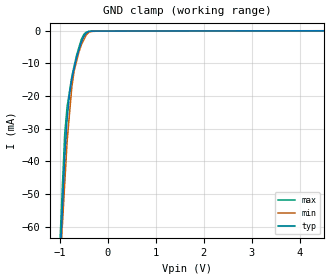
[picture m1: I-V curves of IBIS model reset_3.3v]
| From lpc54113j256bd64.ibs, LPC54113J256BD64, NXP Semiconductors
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[Model] reset_3.3v
Model_type Input
Vinl = 990.000mV
Vinh = 2.64000V
C_comp 1.42000pF 1.40000pF 1.44000pF
[Model spec]
| variable typ   min   max
Vinl  0.990  0.900  1.080
Vinh  2.640  2.400  2.880
| variable typ   min   max
[Voltage Range] 3.30000V 3.00000V 3.60000V
[POWER Clamp Reference] 3.30000V 3.00000V 3.60000V
[GND Clamp Reference] 0.00000V 0.00000V 0.00000V
[Temperature Range]   25   85   -40
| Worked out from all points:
|   GND clamp passes 1 mA (typ) near -0.46 V on its own axis
[GND Clamp]
-3.3V     -822.8mA   -671.3mA   -836.1mA
-900mV    -39.05mA   -47.08mA   -31.79mA
-850mV    -27.19mA   -34.07mA   -23.3mA
-800mV    -19.55mA   -25.55mA   -18.58mA
-750mV    -14.61mA   -17.02mA   -13.87mA
-700mV    -11.38mA   -12.11mA   -10.61mA
-600mV    -5.727mA   -6.359mA   -4.926mA
-550mV    -3.3mA     -4.161mA   -2.506mA
-450mV    -713uA     -1.236mA   -382uA
-350mV    -105.8uA   -196uA     -119.7uA
-175mV    -73.09uA   -68.51uA   -73.7uA
6.6V      69.2uA     79.61uA    61.81uA
[POWER Clamp]
-3.3V     0A         0A         0A
6.6V      0A         0A         0A
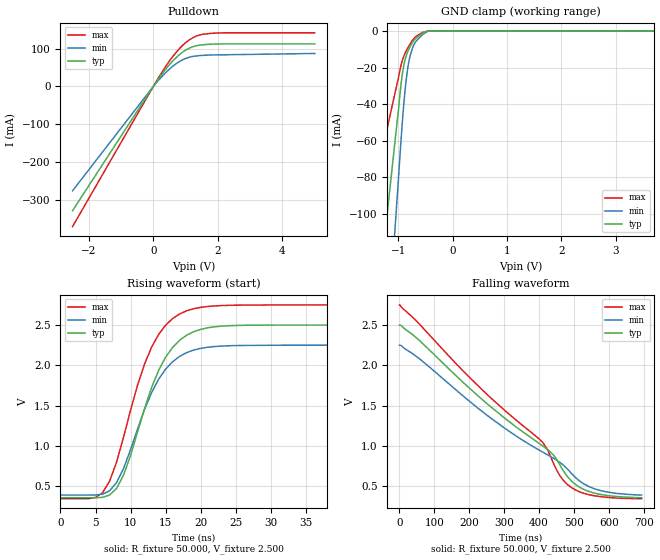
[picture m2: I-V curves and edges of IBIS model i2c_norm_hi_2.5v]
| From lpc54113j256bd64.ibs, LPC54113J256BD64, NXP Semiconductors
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[Model]   i2c_norm_hi_2.5v
Model_type I/O_open_drain
Vinl=4.000E-01
Vinh=1.500E+00
Vref=2.500E+00
Rref=1.000E+03
Cref=0.000E+00
Vmeas=1.250E+00
C_comp   9.060E-12   8.700E-12   9.420E-12
[Voltage Range]   2.500E+00   2.250E+00   2.750E+00
[POWER Clamp Reference]   2.500E+00   2.250E+00   2.750E+00
[GND Clamp Reference]   0.000E+00   0.000E+00   0.000E+00
[Pullup Reference]   2.500E+00   2.250E+00   2.750E+00
[Pulldown Reference]   0.000E+00   0.000E+00   0.000E+00
[Temperature Range]   25   105   -40
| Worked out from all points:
|   slope of the pulldown table from 0 to 0.375 V, typ, clamps not added: 8.44 ohm
|   GND clamp passes 1 mA (typ) near -0.53 V on its own axis
|   rising waveform, R_fixture 50.000, V_fixture 2.500: 20-80 % time 5.21ns typ, 5.22ns min, 5.18ns max; typ from 0.359 V to 2.5 V
|   falling waveform, R_fixture 50.000, V_fixture 2.500: 20-80 % time 342ns typ, 356ns min, 328ns max; typ from 2.5 V to 0.359 V
[GND Clamp]
-2.5V     -459.3mA   -735.3mA   -227.3mA
-1.02V    -49.73mA   -91.54mA   -28.76mA
-1V       -44.89mA   -83.18mA   -26.49mA
-960mV    -32.38mA   -65.07mA   -20.3mA
-920mV    -22.82mA   -48.44mA   -15.76mA
-860mV    -14.29mA   -28.61mA   -11.29mA
-820mV    -10.94mA   -19.54mA   -9.041mA
-780mV    -8.49mA    -13.47mA   -7.044mA
-720mV    -5.59mA    -8.124mA   -4.402mA
-560mV    -1.408mA   -2.144mA   -897uA
-440mV    0A         0A         0A
5V        0A         0A         0A
[Pulldown]
-2.5V     -328.1mA   -275.5mA   -370.2mA
160mV     20.09mA    16.31mA    23.08mA
600mV     67.25mA    53.36mA    78.96mA
860mV     87.65mA    68.38mA    104.5mA
1.04V     98.07mA    75.37mA    118.5mA
1.24V     105.4mA    79.69mA    129.4mA
1.42V     108.9mA    81.45mA    135.7mA
1.86V     112mA      83.37mA    140.8mA
5V        112.5mA    87.24mA    141.8mA
[Rising Waveform]
R_fixture = 50.000
V_fixture = 2.500
V_fixture_min = 2.250
V_fixture_max = 2.750
|  time   V(typ)   V(min)   V(max)
0s        359.4mV    392.6mV    347.6mV
5ns       359.1mV    393mV      363.3mV
7ns       392.5mV    444.7mV    563.3mV
8ns       474.9mV    546.8mV    799.4mV
11ns      1.175V     1.213V     1.756V
13ns      1.726V     1.663V     2.227V
15ns      2.102V     1.954V     2.499V
17ns      2.312V     2.112V     2.638V
23ns      2.487V     2.24V      2.742V
53ns      2.5V       2.25V      2.75V
[Falling Waveform]
R_fixture = 50.000
V_fixture = 2.500
V_fixture_min = 2.250
V_fixture_max = 2.750
|  time   V(typ)   V(min)   V(max)
0s        2.5V       2.25V      2.75V
57ns      2.31V      2.084V     2.514V
236ns     1.582V     1.433V     1.702V
410ns     1.004V     926.7mV    1.048V
424ns     958mV      892mV      960.4mV
457ns     785.9mV    805.2mV    652.6mV
484ns     608.6mV    702.6mV    513.8mV
519ns     483.2mV    557.7mV    427.8mV
559ns     416.7mV    470.4mV    383.6mV
694ns     359.4mV    392.6mV    347.6mV
[Ramp]
dV/dt_r   1.2844E+00/5.1580E-09   1.1140E+00/5.1680E-09   1.3766E+00/5.1440E-09
dV/dt_f   1.2844E+00/3.4247E-07   1.1140E+00/3.5622E-07   1.3766E+00/3.2824E-07
R_load = 50
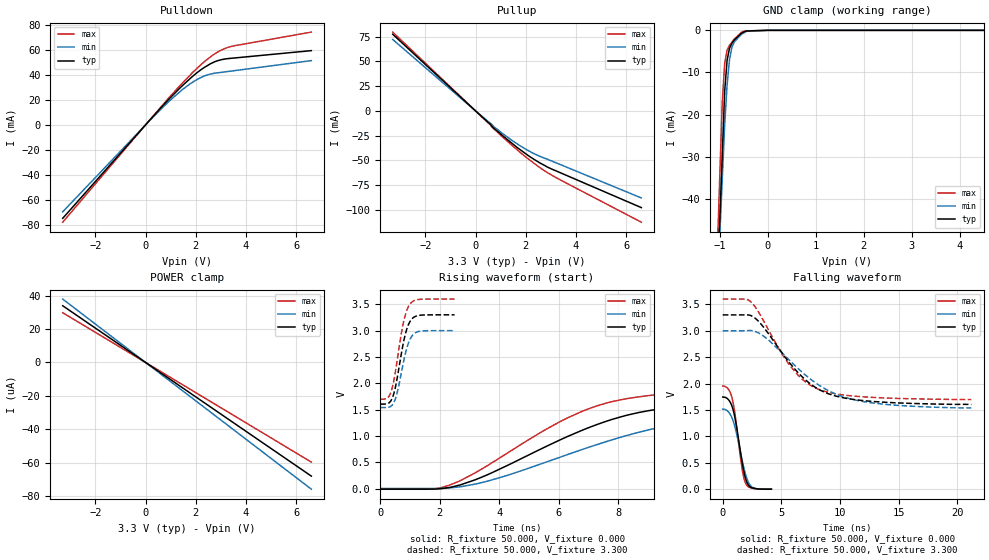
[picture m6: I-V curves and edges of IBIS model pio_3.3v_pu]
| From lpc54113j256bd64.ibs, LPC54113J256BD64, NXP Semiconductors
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[Model]   pio_3.3v_pu
Model_type I/O
Vinl=8.000E-01
Vinh=2.000E+00
Vref=0.000E+00
Rref=1.000E+06
Cref=2.000E-11
Vmeas=1.650E+00
C_comp   9.060E-13   8.700E-13   9.240E-13
[Voltage Range]   3.300E+00   3.000E+00   3.600E+00
[POWER Clamp Reference]   3.300E+00   3.000E+00   3.600E+00
[GND Clamp Reference]   0.000E+00   0.000E+00   0.000E+00
[Pullup Reference]   3.300E+00   3.000E+00   3.600E+00
[Pulldown Reference]   0.000E+00   0.000E+00   0.000E+00
[Temperature Range]   25   105   -40
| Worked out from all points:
|   slope of the pulldown table from 0 to 0.495 V, typ, clamps not added: 44.8 ohm
|   slope of the pullup table from 0 to 0.495 V, typ, clamps not added: 43.6 ohm
|   GND clamp passes 1 mA (typ) near -0.58 V on its own axis
|   rising waveform, R_fixture 50.000, V_fixture 0.000: 20-80 % time 4.35ns typ, 5.29ns min, 3.74ns max; typ from -0.012 V to 1.73 V
|   falling waveform, R_fixture 50.000, V_fixture 0.000: 20-80 % time 788ps typ, 920ps min, 704ps max; typ from 1.75 V to 0.002 V
|   rising waveform, R_fixture 50.000, V_fixture 3.300: 20-80 % time 341ps typ, 343ps min, 341ps max; typ from 1.6 V to 3.3 V
|   falling waveform, R_fixture 50.000, V_fixture 3.300: 20-80 % time 3.95ns typ, 4.88ns min, 3.41ns max; typ from 3.3 V to 1.6 V
[GND Clamp]
-3.3V     -735mA     -639.7mA   -812.5mA
-950mV    -29.46mA   -35.33mA   -17.06mA
-900mV    -14.45mA   -22.48mA   -7.838mA
-850mV    -7.167mA   -13.05mA   -4.739mA
-800mV    -4.27mA    -7.013mA   -3.572mA
-750mV    -3.082mA   -4.05mA    -2.806mA
-700mV    -2.312mA   -2.747mA   -2.039mA
-550mV    -689.6uA   -927.9uA   -494.3uA
-500mV    -362.1uA   -605.4uA   -236.4uA
-400mV    -150.5uA   -141.3uA   -108.2uA
0V        0A         0A         0A
6.6V      0A         0A         0A
[Power Clamp]
-3.3V     34uA       38uA       29.8uA
0V        0A         0A         0A
6.6V      -68.1uA    -75.93uA   -59.69uA
[Pullup]
-3.3V     77.49mA    72.2mA     79.65mA
760mV     -18.12mA   -16.61mA   -18.86mA
1.46V     -32.91mA   -29.95mA   -34.98mA
2.12V     -45.48mA   -40.34mA   -48.91mA
2.58V     -52.8mA    -46.08mA   -57.61mA
3.14V     -59.87mA   -51.73mA   -66.48mA
6.6V      -97.67mA   -87.89mA   -112.4mA
[Pulldown]
-3.3V     -74.59mA   -69.4mA    -77.67mA
140mV     3.186mA    2.948mA    3.327mA
940mV     20.73mA    18.9mA     21.9mA
1.44V     30.86mA    27.69mA    32.8mA
1.78V     37.07mA    32.83mA    39.81mA
2.24V     44.5mA     38.17mA    48.65mA
2.78V     50.6mA     41.38mA    57.01mA
3.34V     53.01mA    42.75mA    62.23mA
6.6V      59.25mA    51.3mA     74.05mA
[Rising Waveform]
R_fixture = 50.000
V_fixture = 0.000
V_fixture_min = 0.000
V_fixture_max = 0.000
|  time   V(typ)   V(min)   V(max)
0s        -11.6mV    1.512mV    -11.05mV
1.75ns    -10.32mV   1.179mV    -6.202mV
2.35ns    23.6mV     13.36mV    69.84mV
3.7ns     286.1mV    155.1mV    469.2mV
6.3ns     989.1mV    645.9mV    1.343V
7.3ns     1.218V     837.1mV    1.572V
8.35ns    1.4V       1.017V     1.713V
10.15ns   1.565V     1.243V     1.825V
12.3ns    1.648V     1.381V     1.882V
20.7ns    1.733V     1.517V     1.939V
[Falling Waveform]
R_fixture = 50.000
V_fixture = 0.000
V_fixture_min = 0.000
V_fixture_max = 0.000
|  time   V(typ)   V(min)   V(max)
0s        1.745V     1.517V     1.953V
450ps     1.705V     1.473V     1.902V
800ps     1.566V     1.347V     1.722V
1.1ns     1.287V     1.13V      1.339V
1.65ns    519.7mV    556.1mV    393.4mV
1.8ns     340.3mV    408.5mV    219.8mV
1.95ns    202.7mV    281.2mV    114.1mV
2.2ns     76.07mV    127.9mV    44.24mV
2.55ns    24.78mV    33.01mV    16.79mV
4.15ns    1.582mV    1.512mV    1.573mV
[Rising Waveform]
R_fixture = 50.000
V_fixture = 3.300
V_fixture_min = 3.000
V_fixture_max = 3.600
|  time   V(typ)   V(min)   V(max)
0s        1.605V     1.538V     1.697V
250ps     1.615V     1.542V     1.724V
400ps     1.711V     1.584V     1.907V
550ps     2.039V     1.781V     2.367V
750ps     2.691V     2.319V     3.076V
850ps     2.949V     2.579V     3.315V
1ns       3.174V     2.835V     3.506V
1.15ns    3.262V     2.948V     3.573V
1.3ns     3.29V      2.985V     3.593V
2.5ns     3.3V       3V         3.6V
[Falling Waveform]
R_fixture = 50.000
V_fixture = 3.300
V_fixture_min = 3.000
V_fixture_max = 3.600
|  time   V(typ)   V(min)   V(max)
0s        3.3V       3V         3.6V
2.4ns     3.287V     3.004V     3.548V
3.45ns    3.078V     2.905V     3.202V
4.85ns    2.646V     2.628V     2.635V
5.8ns     2.365V     2.418V     2.323V
6.9ns     2.102V     2.191V     2.059V
8.15ns    1.896V     1.979V     1.894V
9.75ns    1.758V     1.791V     1.802V
12.1ns    1.675V     1.655V     1.747V
21.2ns    1.605V     1.538V     1.697V
[Ramp]
dV/dt_r   1.0470E+00/4.3389E-09   9.0819E-01/5.2888E-09   1.1703E+00/3.7398E-09
dV/dt_f   1.0173E+00/3.9512E-09   8.7689E-01/4.8527E-09   1.1419E+00/3.3989E-09
R_load = 50
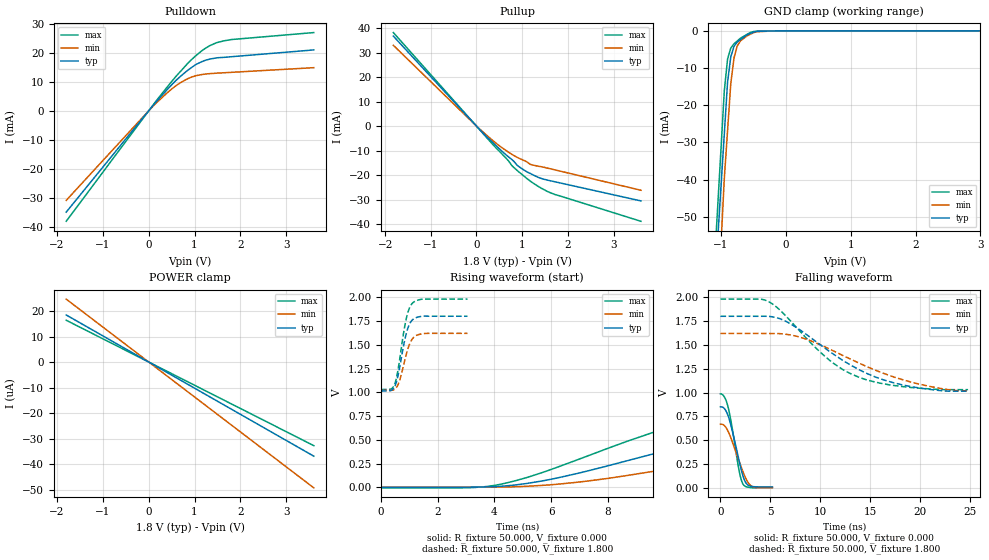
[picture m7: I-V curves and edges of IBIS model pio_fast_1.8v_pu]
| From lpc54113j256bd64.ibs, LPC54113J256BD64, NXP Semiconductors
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[Model]   pio_fast_1.8v_pu
Model_type I/O
Vinl=4.000E-01
Vinh=1.500E+00
Vref=0.000E+00
Rref=1.000E+06
Cref=2.000E-11
Vmeas=9.000E-01
C_comp   9.060E-12   8.700E-12   9.420E-12
[Voltage Range]   1.800E+00   1.620E+00   1.980E+00
[POWER Clamp Reference]   1.800E+00   1.620E+00   1.980E+00
[GND Clamp Reference]   0.000E+00   0.000E+00   0.000E+00
[Pullup Reference]   1.800E+00   1.620E+00   1.980E+00
[Pulldown Reference]   0.000E+00   0.000E+00   0.000E+00
[Temperature Range]   25   105   -40
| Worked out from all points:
|   slope of the pulldown table from 0 to 0.27 V, typ, clamps not added: 54.4 ohm
|   slope of the pullup table from 0 to 0.27 V, typ, clamps not added: 52.3 ohm
|   GND clamp passes 1 mA (typ) near -0.59 V on its own axis
|   rising waveform, R_fixture 50.000, V_fixture 0.000: 20-80 % time 7.6ns typ, 8.94ns min, 6.14ns max; typ from 0.001 V to 0.845 V
|   falling waveform, R_fixture 50.000, V_fixture 0.000: 20-80 % time 1.13ns typ, 1.38ns min, 947ps max; typ from 0.85 V to 0.009 V
|   rising waveform, R_fixture 50.000, V_fixture 1.800: 20-80 % time 315ps typ, 326ps min, 312ps max; typ from 1.01 V to 1.8 V
|   falling waveform, R_fixture 50.000, V_fixture 1.800: 20-80 % time 7.15ns typ, 8.09ns min, 5.95ns max; typ from 1.8 V to 1.01 V
[GND Clamp]
-1.8V     -263.7mA   -335.6mA   -275.8mA
-950mV    -27.75mA   -39.74mA   -16.17mA
-900mV    -13.87mA   -26.94mA   -7.61mA
-850mV    -6.971mA   -14.14mA   -4.632mA
-800mV    -4.156mA   -7.28mA    -3.484mA
-750mV    -2.988mA   -4.044mA   -2.731mA
-700mV    -2.361mA   -2.687mA   -1.978mA
-600mV    -1.106mA   -1.378mA   -966uA
-550mV    -718uA     -946.2uA   -460.3uA
-450mV    -144.5uA   -255.5uA   -88.61uA
0V        0A         0A         0A
3.6V      0A         0A         0A
[Power Clamp]
-1.8V     18.45uA    24.66uA    16.39uA
0V        0A         0A         0A
3.6V      -36.9uA    -49.32uA   -32.77uA
[Pullup]
-1.82V    36.68mA    32.95mA    38.14mA
60mV      -1.186mA   -1.045mA   -1.256mA
520mV     -9.605mA   -8.289mA   -10.63mA
680mV     -12.23mA   -10.39mA   -13.75mA
780mV     -13.74mA   -11.58mA   -16.2mA
900mV     -16.13mA   -12.84mA   -18.25mA
1V        -17.45mA   -13.7mA    -19.78mA
1.2V      -19.53mA   -15.73mA   -22.73mA
1.42V     -21.36mA   -16.58mA   -25.34mA
1.62V     -22.32mA   -17.43mA   -27.21mA
3.6V      -30.52mA   -26.17mA   -38.83mA
[Pulldown]
-1.8V     -34.9mA    -30.86mA   -38.06mA
0V        0A         0A         0A
400mV     7.25mA     6.14mA     8.117mA
600mV     10.52mA    8.704mA    11.94mA
820mV     13.55mA    10.8mA     15.78mA
1.02V     15.83mA    12.03mA    18.86mA
1.16V     16.92mA    12.47mA    20.67mA
1.32V     17.75mA    12.77mA    22.31mA
1.48V     18.2mA     12.94mA    23.43mA
1.8V      18.6mA     13.23mA    24.51mA
3.6V      20.95mA    14.84mA    26.92mA
[Rising Waveform]
R_fixture = 50.000
V_fixture = 0.000
V_fixture_min = 0.000
V_fixture_max = 0.000
|  time   V(typ)   V(min)   V(max)
0s        997.3uV    1.378mV    -5.148mV
3.15ns    2.024mV    1.625mV    -3.175mV
4.25ns    12.16mV    3.223mV    34.99mV
6.25ns    101.2mV    33.85mV    215.6mV
10.3ns    405.7mV    203.6mV    644.2mV
11.85ns   515.3mV    283.4mV    763.1mV
13.5ns    613.2mV    364.9mV    849.4mV
16ns      719mV      471.5mV    919.6mV
18.35ns   778mV      549.8mV    952.7mV
25.05ns   844.6mV    666.9mV    979.7mV
[Falling Waveform]
R_fixture = 50.000
V_fixture = 0.000
V_fixture_min = 0.000
V_fixture_max = 0.000
|  time   V(typ)   V(min)   V(max)
0s        849.9mV    666.9mV    985.7mV
400ps     830.4mV    652.4mV    952mV
750ps     759.7mV    596.2mV    852.3mV
1.15ns    611.8mV    492.7mV    642mV
1.85ns    291.4mV    285.4mV    189.8mV
2.05ns    202.3mV    226.4mV    95.82mV
2.25ns    126.3mV    169.7mV    40.35mV
2.6ns     43.82mV    85.56mV    10.34mV
3.15ns    14.29mV    15.08mV    189.3uV
5.2ns     9.033mV    1.378mV    951.5uV
[Rising Waveform]
R_fixture = 50.000
V_fixture = 1.800
V_fixture_min = 1.620
V_fixture_max = 1.980
|  time   V(typ)   V(min)   V(max)
0s        1.014V     1.019V     1.03V
350ps     1.019V     1.02V      1.035V
500ps     1.069V     1.035V     1.099V
650ps     1.246V     1.116V     1.327V
800ps     1.495V     1.287V     1.629V
900ps     1.628V     1.408V     1.785V
1ns       1.714V     1.501V     1.884V
1.1ns     1.759V     1.559V     1.935V
1.55ns    1.801V     1.619V     1.98V
3.05ns    1.8V       1.62V      1.98V
[Falling Waveform]
R_fixture = 50.000
V_fixture = 1.800
V_fixture_min = 1.620
V_fixture_max = 1.980
|  time   V(typ)   V(min)   V(max)
0s        1.8V       1.62V      1.98V
4ns       1.8V       1.62V      1.98V
4.95ns    1.798V     1.619V     1.946V
7.05ns    1.718V     1.603V     1.747V
10.75ns   1.444V     1.464V     1.354V
12.2ns    1.341V     1.391V     1.244V
13.95ns   1.236V     1.305V     1.157V
18.75ns   1.069V     1.119V     1.056V
22.65ns   1.015V     1.032V     1.03V
24.8ns    1.014V     1.019V     1.03V
[Ramp]
dV/dt_r   5.0453E-01/7.5936E-09   4.0062E-01/8.9309E-09   5.9090E-01/6.1396E-09
dV/dt_f   4.7142E-01/7.1409E-09   3.6076E-01/8.0730E-09   5.6989E-01/5.9432E-09
R_load = 50
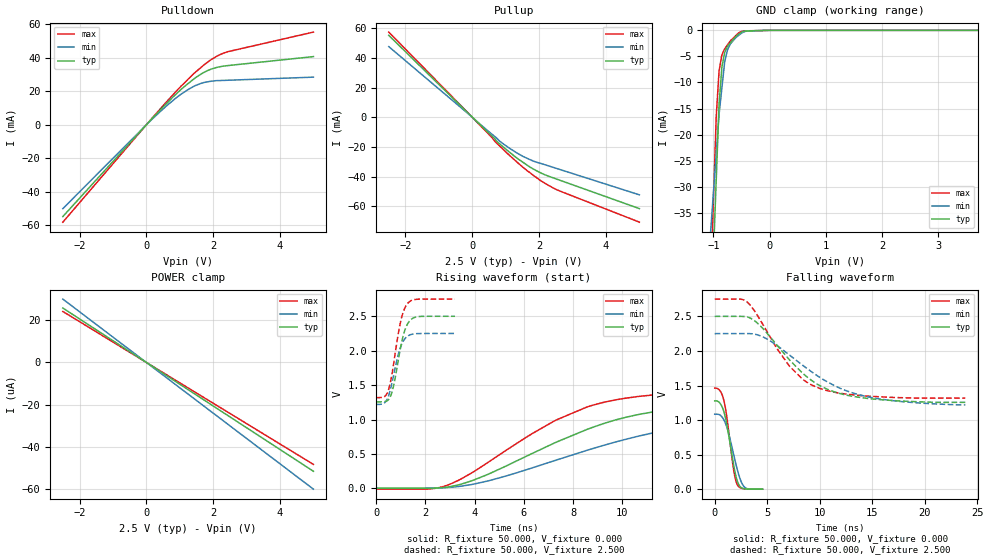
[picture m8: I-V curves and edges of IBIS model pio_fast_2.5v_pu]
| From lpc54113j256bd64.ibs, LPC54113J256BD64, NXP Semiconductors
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[Model]   pio_fast_2.5v_pu
Model_type I/O
Vinl=4.000E-01
Vinh=1.500E+00
Vref=0.000E+00
Rref=1.000E+06
Cref=2.000E-11
Vmeas=1.250E+00
C_comp   9.060E-12   8.700E-12   9.420E-12
[Voltage Range]   2.500E+00   2.250E+00   2.750E+00
[POWER Clamp Reference]   2.500E+00   2.250E+00   2.750E+00
[GND Clamp Reference]   0.000E+00   0.000E+00   0.000E+00
[Pullup Reference]   2.500E+00   2.250E+00   2.750E+00
[Pulldown Reference]   0.000E+00   0.000E+00   0.000E+00
[Temperature Range]   25   105   -40
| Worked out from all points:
|   slope of the pulldown table from 0 to 0.375 V, typ, clamps not added: 46.9 ohm
|   slope of the pullup table from 0 to 0.375 V, typ, clamps not added: 46.2 ohm
|   GND clamp passes 1 mA (typ) near -0.58 V on its own axis
|   rising waveform, R_fixture 50.000, V_fixture 0.000: 20-80 % time 5.16ns typ, 6.52ns min, 4.28ns max; typ from 0.001 V to 1.28 V
|   falling waveform, R_fixture 50.000, V_fixture 0.000: 20-80 % time 884ps typ, 1.06ns min, 766ps max; typ from 1.28 V to 0.001 V
|   rising waveform, R_fixture 50.000, V_fixture 2.500: 20-80 % time 409ps typ, 413ps min, 406ps max; typ from 1.26 V to 2.5 V
|   falling waveform, R_fixture 50.000, V_fixture 2.500: 20-80 % time 4.91ns typ, 6.27ns min, 4.01ns max; typ from 2.5 V to 1.26 V
[GND Clamp]
-2.5V     -475.7mA   -255.8mA   -509.6mA
-950mV    -28.56mA   -23.6mA    -16.48mA
-900mV    -14.13mA   -16.11mA   -7.789mA
-850mV    -7.08mA    -11.07mA   -4.709mA
-800mV    -4.224mA   -6.027mA   -3.542mA
-750mV    -3.043mA   -3.75mA    -2.78mA
-700mV    -2.406mA   -2.615mA   -2.018mA
-600mV    -1.132mA   -1.373mA   -993uA
-500mV    -345.9uA   -523.1uA   -221.8uA
-400mV    -135.5uA   -126.9uA   -93.31uA
0V        0A         0A         0A
5V        0A         0A         0A
[Power Clamp]
-2.5V     25.73uA    29.96uA    24.11uA
0V        0A         0A         0A
5V        -51.47uA   -59.93uA   -48.22uA
[Pullup]
-2.5V     55.17mA    47.6mA     57.37mA
0V        0A         0A         0A
820mV     -17.99mA   -16.12mA   -19.39mA
1.4V      -28.61mA   -24.91mA   -31.48mA
1.94V     -36.26mA   -30.42mA   -40.98mA
2.26V     -39.55mA   -32.62mA   -45.65mA
2.54V     -41.8mA    -34.63mA   -48.95mA
5V        -61.57mA   -52.31mA   -70.72mA
[Pulldown]
-2.5V     -54.85mA   -50.1mA    -58.2mA
0V        0A         0A         0A
500mV     10.6mA     9.452mA    11.41mA
1.04V     21.22mA    18.33mA    23.13mA
1.42V     27.38mA    22.99mA    30.62mA
1.64V     30.38mA    24.79mA    34.37mA
1.84V     32.48mA    25.72mA    37.54mA
2.12V     34.38mA    26.41mA    41.13mA
2.44V     35.42mA    26.64mA    43.72mA
5V        40.78mA    28.5mA     55.43mA
[Rising Waveform]
R_fixture = 50.000
V_fixture = 0.000
V_fixture_min = 0.000
V_fixture_max = 0.000
|  time   V(typ)   V(min)   V(max)
0s        1.249mV    1.217mV    -10.9mV
2.1ns     1.222mV    2.349mV    -9.946mV
2.9ns     19.48mV    12.39mV    47.42mV
4.5ns     197.9mV    104.8mV    367mV
7.35ns    676.6mV    415.2mV    999.4mV
8.6ns     861.4mV    556.9mV    1.186V
9.85ns    1.006V     685.9mV    1.294V
11.6ns    1.129V     832.3mV    1.368V
14.65ns   1.221V     977.3mV    1.423V
23.65ns   1.278V     1.085V     1.452V
[Falling Waveform]
R_fixture = 50.000
V_fixture = 0.000
V_fixture_min = 0.000
V_fixture_max = 0.000
|  time   V(typ)   V(min)   V(max)
0s        1.278V     1.085V     1.462V
500ps     1.244V     1.073V     1.425V
900ps     1.107V     995.2mV    1.265V
1.2ns     897.7mV    874.3mV    992.1mV
1.8ns     352.8mV    503.4mV    282.2mV
1.95ns    236mV      405.9mV    159.7mV
2.15ns    118.5mV    283.4mV    65.57mV
2.55ns    21.09mV    98.55mV    14.59mV
2.9ns     5.062mV    23.42mV    4.224mV
4.55ns    1.249mV    1.217mV    1.229mV
[Rising Waveform]
R_fixture = 50.000
V_fixture = 2.500
V_fixture_min = 2.250
V_fixture_max = 2.750
|  time   V(typ)   V(min)   V(max)
0s        1.257V     1.22V      1.318V
400ps     1.265V     1.268V     1.355V
500ps     1.289V     1.344V     1.432V
600ps     1.355V     1.47V      1.581V
750ps     1.566V     1.718V     1.912V
950ps     1.972V     2.011V     2.354V
1.1ns     2.223V     2.14V      2.565V
1.25ns    2.374V     2.205V     2.675V
1.65ns    2.492V     2.248V     2.747V
3.2ns     2.5V       2.25V      2.75V
[Falling Waveform]
R_fixture = 50.000
V_fixture = 2.500
V_fixture_min = 2.250
V_fixture_max = 2.750
|  time   V(typ)   V(min)   V(max)
0s        2.5V       2.25V      2.75V
2.5ns     2.5V       2.25V      2.749V
3.1ns     2.491V     2.251V     2.705V
4.7ns     2.305V     2.195V     2.352V
7.1ns     1.873V     1.942V     1.783V
8.35ns    1.68V      1.795V     1.593V
9.7ns     1.524V     1.648V     1.475V
12.25ns   1.371V     1.44V      1.381V
14.9ns    1.307V     1.327V     1.343V
23.85ns   1.257V     1.22V      1.318V
[Ramp]
dV/dt_r   7.6469E-01/5.1563E-09   6.4858E-01/6.5173E-09   8.7806E-01/4.2483E-09
dV/dt_f   7.4600E-01/4.9050E-09   6.1833E-01/6.2646E-09   8.5930E-01/3.9848E-09
R_load = 50
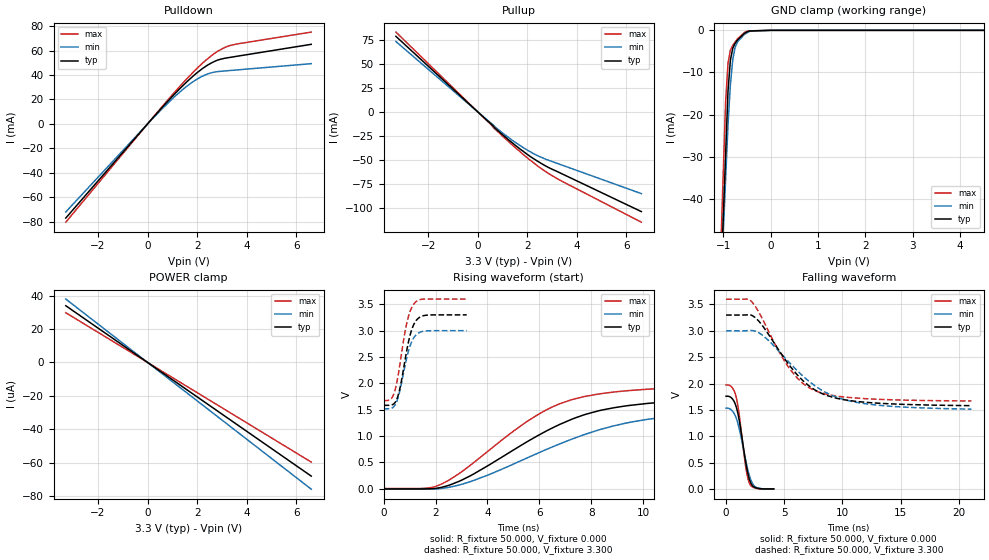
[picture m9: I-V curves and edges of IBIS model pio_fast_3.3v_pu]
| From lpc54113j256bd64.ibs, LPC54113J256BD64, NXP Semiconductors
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[Model]   pio_fast_3.3v_pu
Model_type I/O
Vinl=8.000E-01
Vinh=2.000E+00
Vref=0.000E+00
Rref=1.000E+06
Cref=2.000E-11
Vmeas=1.650E+00
C_comp   9.060E-12   8.700E-12   9.420E-12
[Voltage Range]   3.300E+00   3.000E+00   3.600E+00
[POWER Clamp Reference]   3.300E+00   3.000E+00   3.600E+00
[GND Clamp Reference]   0.000E+00   0.000E+00   0.000E+00
[Pullup Reference]   3.300E+00   3.000E+00   3.600E+00
[Pulldown Reference]   0.000E+00   0.000E+00   0.000E+00
[Temperature Range]   25   105   -40
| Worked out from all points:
|   slope of the pulldown table from 0 to 0.495 V, typ, clamps not added: 43.7 ohm
|   slope of the pullup table from 0 to 0.495 V, typ, clamps not added: 42.9 ohm
|   GND clamp passes 1 mA (typ) near -0.58 V on its own axis
|   rising waveform, R_fixture 50.000, V_fixture 0.000: 20-80 % time 4.01ns typ, 4.87ns min, 3.42ns max; typ from -0.007 V to 1.75 V
|   falling waveform, R_fixture 50.000, V_fixture 0.000: 20-80 % time 778ps typ, 900ps min, 693ps max; typ from 1.76 V to 0.002 V
|   rising waveform, R_fixture 50.000, V_fixture 3.300: 20-80 % time 406ps typ, 410ps min, 403ps max; typ from 1.58 V to 3.3 V
|   falling waveform, R_fixture 50.000, V_fixture 3.300: 20-80 % time 3.75ns typ, 4.6ns min, 3.19ns max; typ from 3.3 V to 1.58 V
[GND Clamp]
-3.3V     -735mA     -639.7mA   -812.5mA
-950mV    -29.46mA   -35.33mA   -17.06mA
-900mV    -14.45mA   -22.48mA   -7.838mA
-850mV    -7.167mA   -13.05mA   -4.739mA
-800mV    -4.27mA    -7.013mA   -3.572mA
-750mV    -3.082mA   -4.05mA    -2.806mA
-700mV    -2.312mA   -2.747mA   -2.039mA
-550mV    -689.6uA   -927.9uA   -494.3uA
-500mV    -362.1uA   -605.4uA   -236.4uA
-400mV    -150.5uA   -141.3uA   -108.2uA
0V        0A         0A         0A
6.6V      0A         0A         0A
[Power Clamp]
-3.3V     34uA       38uA       29.8uA
0V        0A         0A         0A
6.6V      -68.1uA    -75.93uA   -59.69uA
[Pullup]
-3.3V     78.3mA     72.94mA    82.7mA
720mV     -17.43mA   -16.13mA   -18.38mA
1.36V     -31.35mA   -28.83mA   -33.53mA
1.82V     -40.62mA   -36.76mA   -43.91mA
2.5V      -52.53mA   -46.42mA   -57.65mA
3.22V     -62.03mA   -53.52mA   -69.47mA
6.6V      -103.4mA   -84.74mA   -114.4mA
[Pulldown]
-3.3V     -77.06mA   -72.09mA   -80.46mA
140mV     3.263mA    3.027mA    3.421mA
1.04V     23.4mA     21.38mA    24.81mA
1.46V     32mA       28.83mA    34.24mA
1.9V      40.22mA    35.44mA    43.55mA
2.22V     45.34mA    39.08mA    49.76mA
2.64V     50.5mA     42.1mA     56.82mA
3.12V     53.7mA     43.29mA    62.54mA
3.54V     55.09mA    44.01mA    65.14mA
6.6V      65.07mA    49.25mA    75.08mA
[Rising Waveform]
R_fixture = 50.000
V_fixture = 0.000
V_fixture_min = 0.000
V_fixture_max = 0.000
|  time   V(typ)   V(min)   V(max)
0s        -6.972mV   -11.77mV   1.55mV
1.65ns    -6.031mV   -11.97mV   7.215mV
2.2ns     18.82mV    -80.67uV   77.82mV
3.35ns    244.8mV    133.1mV    446.1mV
5.9ns     994.4mV    663.1mV    1.392V
6.8ns     1.222V     850.9mV    1.614V
7.8ns     1.413V     1.036V     1.755V
9.5ns     1.581V     1.26V      1.863V
11.85ns   1.675V     1.403V     1.925V
20.45ns   1.751V     1.522V     1.975V
[Falling Waveform]
R_fixture = 50.000
V_fixture = 0.000
V_fixture_min = 0.000
V_fixture_max = 0.000
|  time   V(typ)   V(min)   V(max)
0s        1.76V      1.536V     1.975V
550ps     1.708V     1.477V     1.917V
900ps     1.54V      1.33V      1.715V
1.15ns    1.281V     1.128V     1.377V
1.7ns     497.4mV    533.1mV    406.8mV
1.85ns    320.2mV    384.7mV    225.2mV
2ns       187.5mV    259.8mV    114.4mV
2.25ns    68.86mV    114.5mV    41.7mV
2.55ns    24.57mV    35.98mV    15.62mV
4.1ns     1.562mV    1.492mV    1.55mV
[Rising Waveform]
R_fixture = 50.000
V_fixture = 3.300
V_fixture_min = 3.000
V_fixture_max = 3.600
|  time   V(typ)   V(min)   V(max)
0s        1.581V     1.514V     1.67V
300ps     1.587V     1.525V     1.711V
400ps     1.612V     1.559V     1.806V
500ps     1.688V     1.647V     1.996V
650ps     1.957V     1.914V     2.438V
900ps     2.65V      2.506V     3.163V
1.05ns    2.971V     2.756V     3.408V
1.2ns     3.154V     2.893V     3.529V
1.6ns     3.291V     2.993V     3.6V
3.2ns     3.3V       3V         3.6V
[Falling Waveform]
R_fixture = 50.000
V_fixture = 3.300
V_fixture_min = 3.000
V_fixture_max = 3.600
|  time   V(typ)   V(min)   V(max)
0s        3.3V       3V         3.6V
2.2ns     3.295V     3.007V     3.555V
3.2ns     3.078V     2.905V     3.196V
4.5ns     2.646V     2.624V     2.624V
5.4ns     2.36V      2.408V     2.303V
6.5ns     2.079V     2.164V     2.023V
7.65ns    1.878V     1.957V     1.866V
9.3ns     1.733V     1.758V     1.771V
11.7ns    1.651V     1.627V     1.718V
21.1ns    1.581V     1.514V     1.67V
[Ramp]
dV/dt_r   1.0546E+00/4.0018E-09   9.2039E-01/4.8626E-09   1.1824E+00/3.4156E-09
dV/dt_f   1.0315E+00/3.7458E-09   8.9139E-01/4.5835E-09   1.1580E+00/3.1818E-09
R_load = 50
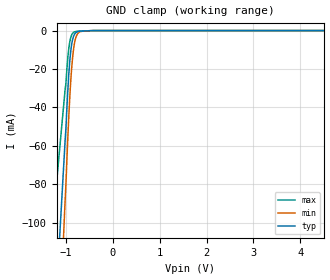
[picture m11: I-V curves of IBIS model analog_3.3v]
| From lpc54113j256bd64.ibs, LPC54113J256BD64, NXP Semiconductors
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[Model] analog_3.3v
Model_type Terminator
C_comp  0.906pF 0.870pF 0.942pF
| variable typ   min   max
[Voltage Range]   3.30000V  3.00000V  3.60000V
[POWER Clamp Reference]  3.30000V  3.00000V  3.60000V
[GND Clamp Reference]   0.00000V  0.00000V  0.00000V
[Temperature Range]   25   85   -40
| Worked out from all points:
|   GND clamp passes 1 mA (typ) near -0.78 V on its own axis
[GND Clamp]
-3.3V     -1.042A    -1.351A    -636.8mA
-1.02V    -58.5mA    -90.25mA   -31.49mA
-1V       -51.02mA   -79.97mA   -27.36mA
-960mV    -31.4mA    -56.23mA   -14.32mA
-920mV    -16.62mA   -35.82mA   -6.182mA
-880mV    -7.597mA   -20.36mA   -2.426mA
-860mV    -4.932mA   -14.66mA   -1.531mA
-820mV    -2.058mA   -6.953mA   -711.8uA
-780mV    -937.2uA   -3.049mA   -455.4uA
-720mV    -390.3uA   -907.4uA   -313.1uA
-440mV    -30.64uA   -39.2uA    -26.15uA
6.6V      0A         0A         0A
[Power Clamp]
-3.3V     0A         0A         0A
0V        0A         0A         0A
3.3V      0A         0A         0A
6.6V      0A         0A         0A
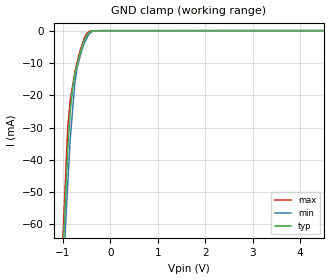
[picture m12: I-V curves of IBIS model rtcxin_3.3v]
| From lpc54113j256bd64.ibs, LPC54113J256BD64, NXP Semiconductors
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[Model] rtcxin_3.3v
Model_type Terminator
C_comp 1.70000pF 1.70000pF 1.70000pF
| variable typ   min   max
[Voltage Range] 3.30000V 3.00000V 3.60000V
[POWER Clamp Reference] 3.30000V 3.00000V 3.60000V
[GND Clamp Reference] 0.00000V 0.00000V 0.00000V
[Temperature Range]   25   85   -40
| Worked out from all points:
|   GND clamp passes 1 mA (typ) near -0.47 V on its own axis
[GND Clamp]
-3.3V     -801.7mA   -703.5mA   -836.9mA
-900mV    -37.14mA   -47.59mA   -29.92mA
-850mV    -25.48mA   -33.92mA   -21.82mA
-800mV    -18.18mA   -25.06mA   -17.33mA
-750mV    -13.5mA    -16.19mA   -12.84mA
-700mV    -10.47mA   -11.33mA   -9.781mA
-600mV    -5.203mA   -5.816mA   -4.476mA
-550mV    -2.959mA   -3.759mA   -2.233mA
-450mV    -592.6uA   -1.069mA   -285.2uA
-350mV    -34.94uA   -121uA     -43.81uA
-175mV    -6.478uA   -7.696uA   -2.769uA
6.6V      13.81uA    23.04uA    8.302uA
[POWER Clamp]
-3.3V     0A         0A         0A
6.6V      0A         0A         0A
